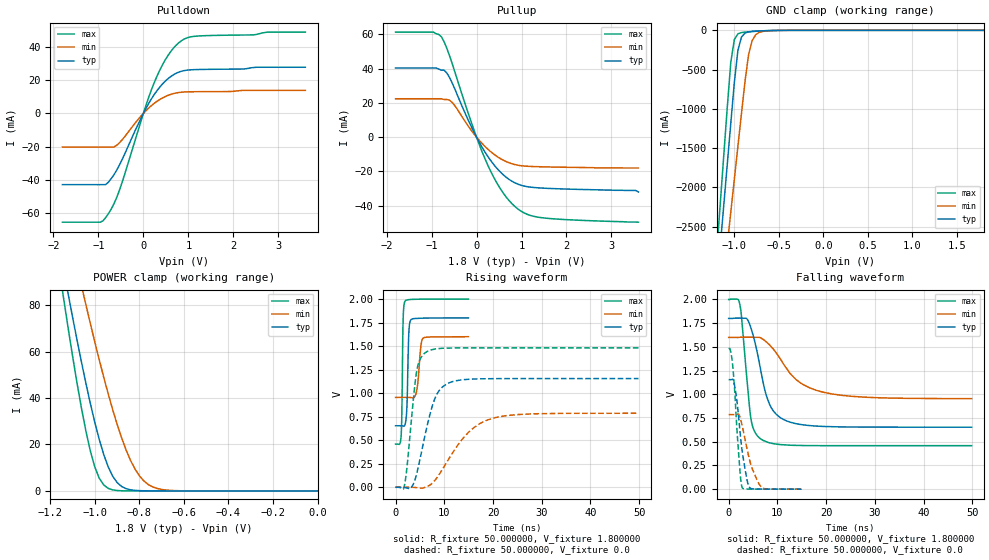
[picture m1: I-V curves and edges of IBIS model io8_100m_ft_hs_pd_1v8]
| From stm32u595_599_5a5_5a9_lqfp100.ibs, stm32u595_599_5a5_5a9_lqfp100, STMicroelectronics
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|   Model io8_100m_ft_hs_pd_1v8
[Model]  io8_100m_ft_hs_pd_1v8
Model_type I/O
Polarity   Non-Inverting
Enable   Active-Low
Vinl =   0.540000V
Vinh =   1.260000V
Vmeas =  0.900000V
Cref =   50.000000pF
Rref =   100.000000M
Vref =   0.0V
C_comp   3.148300pF   3.147400pF   3.196500pF
[Temperature Range]   25.000000   0.140000k   -40.000000
[Pullup Reference]   1.800000V   1.600000V   2.000000V
[Pulldown Reference]   0.0V   0.0V   0.0V
[POWER Clamp Reference]   1.800000V   1.600000V   2.000000V
[GND Clamp Reference]   0.0V   0.0V   0.0V
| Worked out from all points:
|   slope of the pulldown table from 0 to 0.27 V, typ, clamps not added: 21.7 ohm
|   slope of the pullup table from 0 to 0.27 V, typ, clamps not added: 22.6 ohm
|   GND clamp passes 1 mA (typ) near -0.51 V on its own axis
|   POWER clamp passes 1 mA (typ) near -0.86 V on its own axis
|   rising waveform, R_fixture 50.000000, V_fixture 1.800000: 20-80 % time 321ps typ, 635ps min, 233ps max; typ from 0.654 V to 1.8 V
|   rising waveform, R_fixture 50.000000, V_fixture 0.0: 20-80 % time 3.21ns typ, 6.77ns min, 1.69ns max; typ from 0 V to 1.15 V
|   falling waveform, R_fixture 50.000000, V_fixture 1.800000: 20-80 % time 3.21ns typ, 6.74ns min, 1.65ns max; typ from 1.8 V to 0.654 V
|   falling waveform, R_fixture 50.000000, V_fixture 0.0: 20-80 % time 1.6ns typ, 2.38ns min, 1.14ns max; typ from 1.15 V to 0 V
[Pulldown]
|Voltage   I(typ)   I(min)   I(max)
-1.8V     -42.74mA   -20.21mA   -65.25mA
-960mV    -42.74mA   -20.21mA   -65.25mA
-780mV    -41.3mA    -20.21mA   -60.25mA
-660mV    -37mA      -20.2mA    -54.5mA
-540mV    -31.39mA   -17.82mA   -46.65mA
0V        0A         100fA      0A
240mV     11.28mA    6.002mA    18.38mA
480mV     19.17mA    10.02mA    31.83mA
780mV     24.67mA    12.5mA     42.21mA
960mV     25.9mA     12.9mA     45.21mA
1.14V     26.24mA    12.99mA    46.23mA
3.6V      27.67mA    13.81mA    48.75mA
[Pullup]
|Voltage   I(typ)   I(min)   I(max)
-1.8V     40.32mA    22.37mA    61.24mA
-960mV    40.32mA    22.37mA    61.24mA
-780mV    39.04mA    22.37mA    58.49mA
-660mV    37.4mA     21.92mA    51.77mA
-540mV    31.51mA    20.18mA    42.78mA
-120mV    6.338mA    4.065mA    8.965mA
240mV     -10.82mA   -6.752mA   -15.73mA
540mV     -20.62mA   -12.68mA   -30.5mA
900mV     -27.22mA   -16.28mA   -41.49mA
1.14V     -28.94mA   -17mA      -45.14mA
1.5V      -29.77mA   -17.34mA   -47.14mA
3.6V      -32mA      -18mA      -49.6mA
[GND_clamp]
|Voltage   I(typ)   I(min)   I(max)
-1.8V     -9.707A    -9.942A    -9.774A
-1.2V     -3.309A    -4.006A    -2.865A
-1.16V    -2.777A    -3.584A    -2.239A
-1.12V    -2.246A    -3.162A    -1.614A
-1.04V    -1.186A    -2.319A    -408.7mA
-1V       -663.9mA   -1.898A    -117.8mA
-960mV    -254mA     -1.478A    -45.15mA
-920mV    -86.04mA   -1.06A     -28.6mA
-840mV    -19.13mA   -308.9mA   -18.75mA
-800mV    -13.4mA    -130.8mA   -15.33mA
-720mV    -7.959mA   -25.38mA   -9.395mA
1.8V      45.71uA    33.33uA    56.11uA
[POWER_clamp]
|Voltage   I(typ)   I(min)   I(max)
-1.8V     470.8mA    433.7mA    554.6mA
-1.14V    95.25mA    122.7mA    82.82mA
-1.12V    84.97mA    114mA      70.27mA
-1.06V    55.51mA    88.42mA    35.67mA
-1.04V    46.34mA    80.15mA    25.76mA
-1V       29.51mA    64.13mA    10.3mA
-940mV    10.39mA    41.86mA    1.109mA
-900mV    3.624mA    28.77mA    182.8uA
-840mV    490.7uA    13.24mA    11.35uA
-800mV    116.8uA    6.532mA    1.77uA
-740mV    13.2uA     1.723mA    109.3nA
0V        0A         18.72nA    0A
[Ramp]
| variable   typ   min   max
dV/dt_r  0.69258/3.20144n   0.47165/6.75160n   0.88830/1.68845n
dV/dt_f  0.68753/3.20925n   0.38675/6.71993n   0.92452/1.65194n
R_load = 50.000000
[Rising Waveform]
R_fixture= 50.000000
V_fixture= 1.800000
V_fixture_min= 1.600000
V_fixture_max= 2.000000
|time   V(typ)   V(min)   V(max)
0s        653.5mV    954.4mV    458.5mV
1.141ns   653.4mV    954.4mV    543mV
1.562ns   650.5mV    954.4mV    1.789V
1.922ns   663.2mV    954.4mV    1.974V
2.312ns   831mV      954.4mV    1.989V
2.763ns   1.673V     954.2mV    1.994V
3.123ns   1.777V     953.3mV    1.995V
4.324ns   1.794V     1.025V     1.997V
5.556ns   1.796V     1.578V     1.998V
14.95ns   1.799V     1.599V     1.999V
[Rising Waveform]
R_fixture= 50.000000
V_fixture= 0.0
V_fixture_min= 0.0
V_fixture_max= 0.0
|time   V(typ)   V(min)   V(max)
0s        3.152uV    2.986uV    1.193uV
1.802ns   -1.584mV   519.2nV    12.74mV
3.103ns   -9.114mV   131.7uV    631.5mV
4.404ns   157.9mV    -4.259mV   1.252V
6.507ns   658.5mV    9.259mV    1.443V
8.008ns   933.5mV    69.3mV     1.467V
9.61ns    1.065V     190mV      1.476V
14.41ns   1.145V     553.3mV    1.48V
18.72ns   1.153V     711.6mV    1.48V
49.85ns   1.154V     786.2mV    1.48V
[Falling Waveform]
R_fixture= 50.000000
V_fixture= 1.800000
V_fixture_min= 1.600000
V_fixture_max= 2.000000
|time   V(typ)   V(min)   V(max)
0s        1.799V     1.599V     1.999V
2.202ns   1.803V     1.601V     1.965V
2.603ns   1.803V     1.602V     1.834V
4.605ns   1.693V     1.602V     732.1mV
7.007ns   1.141V     1.581V     515.5mV
8.408ns   892.7mV    1.519V     488.5mV
10.11ns   773.3mV    1.411V     473mV
13.91ns   689.5mV    1.151V     461.5mV
18.52ns   663.5mV    1.034V     458.9mV
49.85ns   653.5mV    954.4mV    458.5mV
[Falling Waveform]
R_fixture= 50.000000
V_fixture= 0.0
V_fixture_min= 0.0
V_fixture_max= 0.0
|time   V(typ)   V(min)   V(max)
0s        1.154V     786.2mV    1.48V
600.6ps   1.155V     786.2mV    1.397V
1.231ns   1.089V     786.1mV    1.042V
1.682ns   934.2mV    787.1mV    641.3mV
2.252ns   644.5mV    769.5mV    233.5mV
2.523ns   507.6mV    722.5mV    79.44mV
2.763ns   404.1mV    670.8mV    18.33mV
4.144ns   29.52mV    339mV      1.272mV
6.787ns   961.9uV    18.43mV    374.8uV
14.95ns   3.152uV    2.986uV    1.193uV
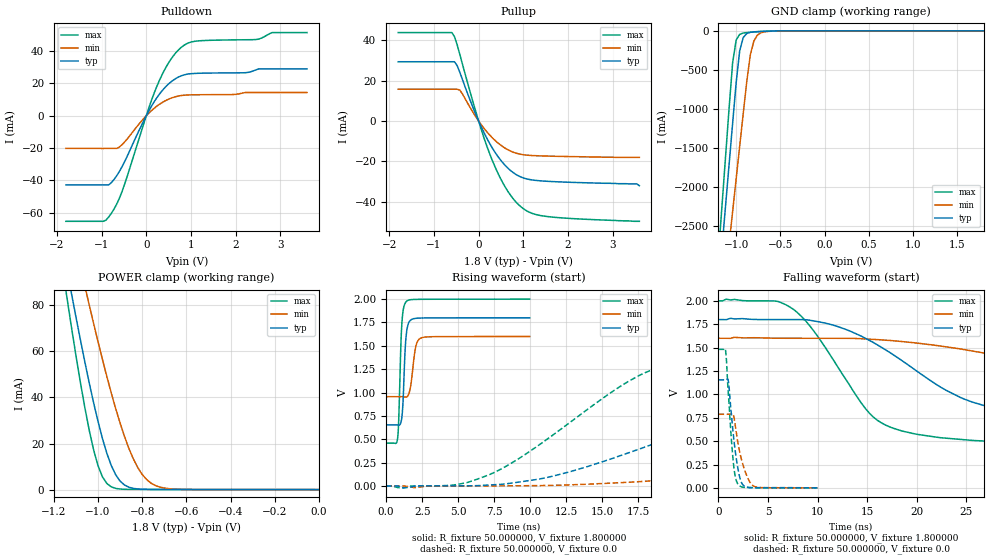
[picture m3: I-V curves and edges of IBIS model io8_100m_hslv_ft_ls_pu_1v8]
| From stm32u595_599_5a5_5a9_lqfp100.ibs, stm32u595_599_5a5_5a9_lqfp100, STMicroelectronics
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|   Model io8_100m_hslv_ft_ls_pu_1v8
[Model]  io8_100m_hslv_ft_ls_pu_1v8
Model_type I/O
Polarity   Non-Inverting
Enable   Active-Low
Vinl =   0.540000V
Vinh =   1.260000V
Vmeas =  0.900000V
Cref =   50.000000pF
Rref =   100.000000M
Vref =   0.0V
C_comp   3.235100pF   3.233100pF   3.282800pF
[Temperature Range]   25.000000   0.140000k   -40.000000
[Pullup Reference]   1.800000V   1.600000V   2.000000V
[Pulldown Reference]   0.0V   0.0V   0.0V
[POWER Clamp Reference]   1.800000V   1.600000V   2.000000V
[GND Clamp Reference]   0.0V   0.0V   0.0V
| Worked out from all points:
|   slope of the pulldown table from 0 to 0.27 V, typ, clamps not added: 21.7 ohm
|   slope of the pullup table from 0 to 0.27 V, typ, clamps not added: 22.6 ohm
|   GND clamp passes 1 mA (typ) near -0.51 V on its own axis
|   POWER clamp passes 1 mA (typ) near -0.86 V on its own axis
|   rising waveform, R_fixture 50.000000, V_fixture 1.800000: 20-80 % time 202ps typ, 314ps min, 189ps max; typ from 0.655 V to 1.8 V
|   rising waveform, R_fixture 50.000000, V_fixture 0.0: 20-80 % time 14.5ns typ, 29.3ns min, 8.35ns max; typ from 0.001 V to 1.16 V
|   falling waveform, R_fixture 50.000000, V_fixture 1.800000: 20-80 % time 11.4ns typ, 24.9ns min, 6.02ns max; typ from 1.8 V to 0.655 V
|   falling waveform, R_fixture 50.000000, V_fixture 0.0: 20-80 % time 736ps typ, 1.01ns min, 582ps max; typ from 1.16 V to 0.001 V
[Pulldown]
|Voltage   I(typ)   I(min)   I(max)
-1.8V     -42.74mA   -20.21mA   -65.25mA
-960mV    -42.74mA   -20.21mA   -65.25mA
-780mV    -41.3mA    -20.21mA   -60.25mA
-540mV    -31.39mA   -17.82mA   -46.65mA
0V        0A         0A         0A
240mV     11.28mA    6.001mA    18.38mA
480mV     19.17mA    10.02mA    31.83mA
780mV     24.67mA    12.49mA    42.21mA
1.14V     26.24mA    12.99mA    46.23mA
2.46V     28.42mA    14.38mA    47.14mA
2.82V     28.99mA    14.38mA    51.44mA
3.6V      28.99mA    14.38mA    51.44mA
[Pullup]
|Voltage   I(typ)   I(min)   I(max)
-1.8V     29.28mA    15.71mA    43.7mA
-600mV    29.28mA    15.71mA    43.7mA
-540mV    29.28mA    15.71mA    41.71mA
-420mV    24.04mA    15.23mA    32.87mA
0V        630fA      250pA      10fA
300mV     -13.1mA    -8.157mA   -19.11mA
600mV     -22.1mA    -13.53mA   -32.82mA
780mV     -25.61mA   -15.48mA   -38.6mA
960mV     -27.82mA   -16.55mA   -42.66mA
1.2V      -29.16mA   -17.08mA   -45.68mA
1.56V     -29.85mA   -17.37mA   -47.3mA
3.6V      -32mA      -18mA      -49.6mA
[GND_clamp]
|Voltage   I(typ)   I(min)   I(max)
-1.8V     -9.707A    -9.942A    -9.774A
-1.2V     -3.309A    -4.006A    -2.864A
-1.16V    -2.777A    -3.584A    -2.239A
-1.12V    -2.246A    -3.162A    -1.614A
-1.04V    -1.186A    -2.319A    -408.6mA
-1V       -663.9mA   -1.898A    -117.8mA
-960mV    -254mA     -1.478A    -45.14mA
-920mV    -86.03mA   -1.06A     -28.58mA
-840mV    -19.12mA   -308.9mA   -18.74mA
-800mV    -13.39mA   -130.8mA   -15.31mA
-720mV    -7.948mA   -25.37mA   -9.381mA
1.8V      0A         14.95nA    0A
[POWER_clamp]
|Voltage   I(typ)   I(min)   I(max)
-1.8V     470.9mA    433.7mA    554.6mA
-1.14V    95.28mA    122.7mA    82.88mA
-1.12V    85mA       114mA      70.34mA
-1.06V    55.55mA    88.43mA    35.73mA
-1.04V    46.38mA    80.17mA    25.83mA
-1V       29.54mA    64.14mA    10.37mA
-940mV    10.43mA    41.88mA    1.177mA
-900mV    3.66mA     28.79mA    250.5uA
-840mV    527.2uA    13.26mA    94.87uA
-800mV    153.8uA    6.55mA     88.76uA
-740mV    60.08uA    1.741mA    70.81uA
0V        0A         18.15nA    0A
[Ramp]
| variable   typ   min   max
dV/dt_r  0.69287/14.45255n   0.47190/29.25934n   0.88855/8.34234n
dV/dt_f  0.68715/11.33826n   0.38628/24.86071n   0.92439/6.00264n
R_load = 50.000000
[Rising Waveform]
R_fixture= 50.000000
V_fixture= 1.800000
V_fixture_min= 1.600000
V_fixture_max= 2.000000
|time   V(typ)   V(min)   V(max)
0s        654.8mV    956.1mV    459.3mV
780.8ps   653.9mV    956mV      496.2mV
860.9ps   651.3mV    956.1mV    664.2mV
1.081ns   724.7mV    956mV      1.715V
1.201ns   1.006V     955.1mV    1.898V
1.401ns   1.626V     952.2mV    1.974V
1.662ns   1.77V      1.037V     1.993V
2.082ns   1.795V     1.507V     1.997V
2.422ns   1.798V     1.584V     1.998V
9.97ns    1.8V       1.6V       2V
[Rising Waveform]
R_fixture= 50.000000
V_fixture= 0.0
V_fixture_min= 0.0
V_fixture_max= 0.0
|time   V(typ)   V(min)   V(max)
0s        611.3uV    688.3uV    577.8uV
6.006ns   2.833mV    1.347mV    56.51mV
11.21ns   93.11mV    6.136mV    504.8mV
18.02ns   420mV      51.05mV    1.215V
21.62ns   613.6mV    101.4mV    1.36V
26.83ns   851.8mV    194.8mV    1.435V
34.03ns   1.037V     335.6mV    1.468V
40.84ns   1.103V     457.1mV    1.478V
71.67ns   1.153V     735mV      1.482V
199.4ns   1.155V     787.4mV    1.482V
[Falling Waveform]
R_fixture= 50.000000
V_fixture= 1.800000
V_fixture_min= 1.600000
V_fixture_max= 2.000000
|time   V(typ)   V(min)   V(max)
0s        1.8V       1.6V       2V
6.807ns   1.8V       1.6V       1.958V
9.209ns   1.793V     1.6V       1.732V
14.41ns   1.622V     1.595V     905.7mV
16.02ns   1.53V      1.586V     723.5mV
19.62ns   1.278V     1.553V     581.6mV
25.63ns   916.7mV    1.463V     507.7mV
42.04ns   705mV      1.156V     465.6mV
64.06ns   663.4mV    1.021V     459.9mV
199.4ns   654.8mV    956.1mV    459.3mV
[Falling Waveform]
R_fixture= 50.000000
V_fixture= 0.0
V_fixture_min= 0.0
V_fixture_max= 0.0
|time   V(typ)   V(min)   V(max)
0s        1.155V     787.4mV    1.482V
720.7ps   1.155V     787.5mV    1.464V
1.001ns   1.137V     787.7mV    995.7mV
1.461ns   604.9mV    790.8mV    312.2mV
1.662ns   417.7mV    689.2mV    137.8mV
1.982ns   193.9mV    468.8mV    37.7mV
2.462ns   32.46mV    248.8mV    7.98mV
3.043ns   5.176mV    85.74mV    3.168mV
3.584ns   1.593mV    17.78mV    2.652mV
9.97ns    611.3uV    688.3uV    577.8uV
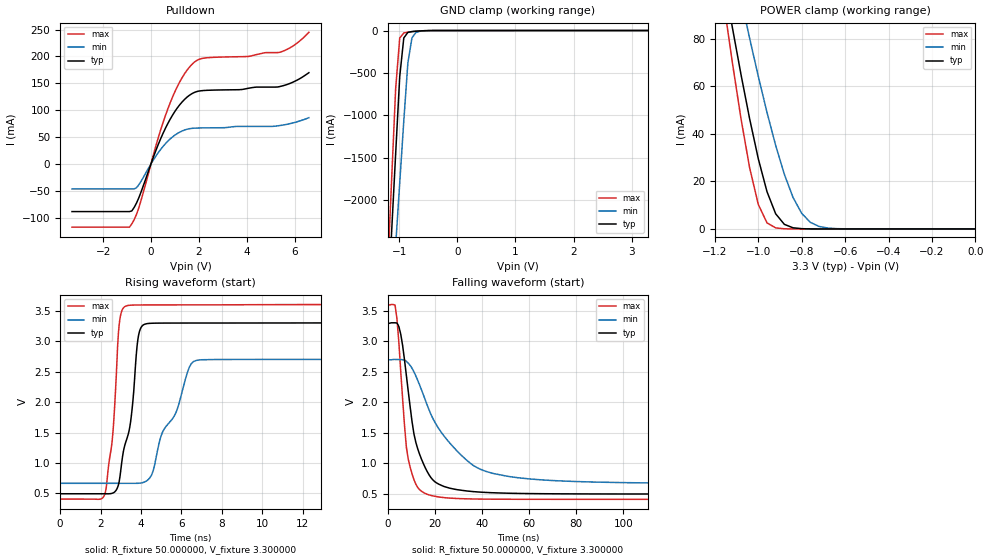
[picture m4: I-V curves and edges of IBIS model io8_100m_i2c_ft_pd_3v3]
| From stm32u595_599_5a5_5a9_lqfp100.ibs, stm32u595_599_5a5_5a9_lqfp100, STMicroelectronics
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|   Model io8_100m_i2c_ft_pd_3v3
[Model]  io8_100m_i2c_ft_pd_3v3
Model_type I/O_open_drain
Polarity   Non-Inverting
Enable   Active-Low
Vinl =   0.990000V
Vinh =   2.310000V
Vmeas =  1.600000V
Cref =   50.000000pF
Rref =   1.000000
Vref =   1.650000V
C_comp   3.320400pF   3.288500pF   3.361100pF
[Temperature Range]   25.000000   0.140000k   -40.000000
[Pullup Reference]   3.300000V   2.700000V   3.600000V
[Pulldown Reference]   0.0V   0.0V   0.0V
[POWER Clamp Reference]   3.300000V   2.700000V   3.600000V
[GND Clamp Reference]   0.0V   0.0V   0.0V
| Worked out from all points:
|   slope of the pulldown table from 0 to 0.495 V, typ, clamps not added: 8.84 ohm
|   GND clamp passes 1 mA (typ) near -0.50 V on its own axis
|   POWER clamp passes 1 mA (typ) near -0.85 V on its own axis
|   rising waveform, R_fixture 50.000000, V_fixture 3.300000: 20-80 % time 691ps typ, 1.39ns min, 418ps max; typ from 0.496 V to 3.3 V
|   falling waveform, R_fixture 50.000000, V_fixture 3.300000: 20-80 % time 7.46ns typ, 19.4ns min, 4.08ns max; typ from 3.3 V to 0.496 V
[Pulldown]
|Voltage   I(typ)   I(min)   I(max)
-3.3V     -88.61mA   -46.48mA   -117.6mA
-900mV    -88.61mA   -46.48mA   -117.6mA
-700mV    -80.76mA   -46.48mA   -103.5mA
-500mV    -62.15mA   -38.24mA   -80.45mA
300mV     35.76mA    20.75mA    48.1mA
800mV     83.04mA    46.39mA    113.5mA
1.3V      115.2mA    61.33mA    160.4mA
1.8V      132.8mA    66.57mA    188.9mA
2.3V      136.9mA    67.16mA    197.4mA
5.4V      144.2mA    71.57mA    207.9mA
6V        153.6mA    77.1mA     221.4mA
6.6V      169.8mA    86.1mA     244.9mA
[GND_clamp]
|Voltage   I(typ)   I(min)   I(max)
-3.3V     -9.848A    -9.957A    -9.458A
-1.2V     -3.312A    -4.013A    -2.863A
-1.13V    -2.381A    -3.274A    -1.769A
-1.06V    -1.452A    -2.535A    -684.8mA
-990mV    -542.9mA   -1.798A    -88.04mA
-920mV    -87.13mA   -1.064A    -28.45mA
-850mV    -22.11mA   -382.4mA   -19.62mA
-780mV    -11.98mA   -86.98mA   -13.73mA
-710mV    -7.63mA    -22.27mA   -8.759mA
-640mV    -4.504mA   -7.781mA   -4.831mA
-360mV    -39.8uA    -178.9uA   -19.56uA
3.28V     83.52uA    56.87uA    102.4uA
[POWER_clamp]
|Voltage   I(typ)   I(min)   I(max)
-3.28V    1.355A     1.167A     1.664A
-1.16V    105.7mA    131.6mA    95.69mA
-1.12V    84.97mA    114mA      70.27mA
-1.08V    65.05mA    96.83mA    46.54mA
-1.04V    46.34mA    80.15mA    25.76mA
-1V       29.51mA    64.13mA    10.3mA
-960mV    15.69mA    48.99mA    2.571mA
-920mV    6.373mA    35.1mA     455.6uA
-840mV    490.7uA    13.24mA    11.36uA
-760mV    27.33uA    2.767mA    276.6nA
-640mV    346.6nA    134.1uA    15.62nA
0V        0A         19.91nA    0A
[Ramp]
| variable   typ   min   max
dV/dt_r  1.68215/0.76969n   1.21927/1.44587n   1.91450/0.52866n
dV/dt_f  1.68215/7.44752n   1.21927/19.36738n   1.91450/4.06989n
R_load = 50.000000
[Rising Waveform]
R_fixture= 50.000000
V_fixture= 3.300000
V_fixture_min= 2.700000
V_fixture_max= 3.600000
|time   V(typ)   V(min)   V(max)
0s        495.6mV    667.1mV    408.3mV
2.202ns   495.4mV    667mV      482.9mV
2.603ns   507mV      666.7mV    1.467V
2.923ns   698.5mV    666.4mV    3.276V
3.243ns   1.34V      666.2mV    3.572V
3.524ns   1.776V     666.3mV    3.589V
3.844ns   3.022V     667.3mV    3.591V
4.164ns   3.273V     687.3mV    3.592V
6.727ns   3.295V     2.681V     3.593V
19.94ns   3.299V     2.699V     3.599V
[Falling Waveform]
R_fixture= 50.000000
V_fixture= 3.300000
V_fixture_min= 2.700000
V_fixture_max= 3.600000
|time   V(typ)   V(min)   V(max)
0s        3.299V     2.699V     3.599V
3.203ns   3.307V     2.705V     3.598V
5.606ns   3.122V     2.704V     2.512V
8.008ns   2.44V      2.673V     1.263V
9.61ns    1.926V     2.607V     935.3mV
12.81ns   1.238V     2.362V     602.9mV
19.22ns   728.1mV    1.738V     464.7mV
37.64ns   531.3mV    935.6mV    413.4mV
64.06ns   501.1mV    731.4mV    408.7mV
398.8ns   495.6mV    667.1mV    408.3mV
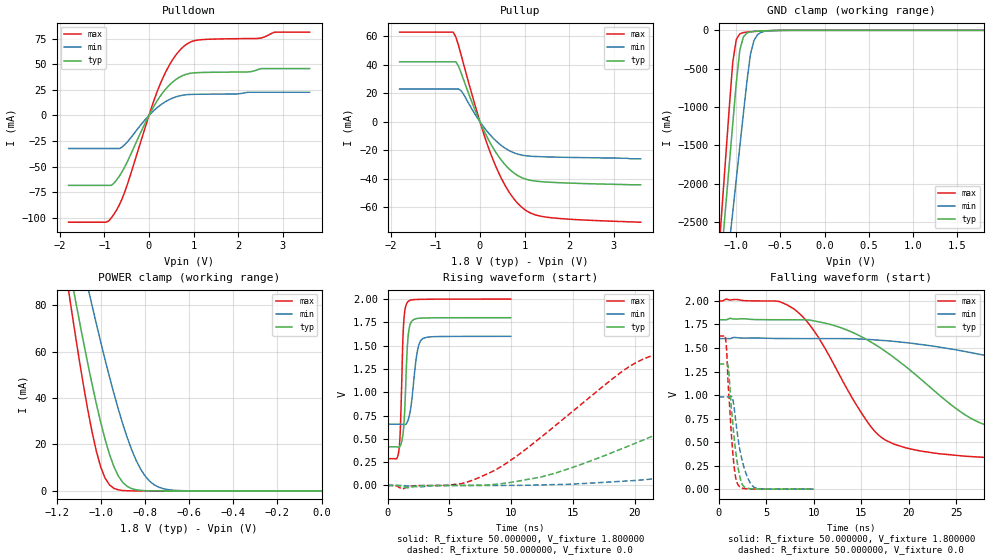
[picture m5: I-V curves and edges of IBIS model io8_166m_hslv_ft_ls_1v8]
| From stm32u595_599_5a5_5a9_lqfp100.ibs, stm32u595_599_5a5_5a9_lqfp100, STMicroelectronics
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|   Model io8_166m_hslv_ft_ls_1v8
[Model]  io8_166m_hslv_ft_ls_1v8
Model_type I/O
Polarity   Non-Inverting
Enable   Active-Low
Vinl =   0.540000V
Vinh =   1.260000V
Vmeas =  0.900000V
Cref =   50.000000pF
Rref =   100.000000M
Vref =   0.0V
C_comp   3.358300pF   3.352700pF   3.400300pF
[Temperature Range]   25.000000   0.140000k   -40.000000
[Pullup Reference]   1.800000V   1.600000V   2.000000V
[Pulldown Reference]   0.0V   0.0V   0.0V
[POWER Clamp Reference]   1.800000V   1.600000V   2.000000V
[GND Clamp Reference]   0.0V   0.0V   0.0V
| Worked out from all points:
|   slope of the pulldown table from 0 to 0.27 V, typ, clamps not added: 13.6 ohm
|   slope of the pullup table from 0 to 0.27 V, typ, clamps not added: 15.9 ohm
|   GND clamp passes 1 mA (typ) near -0.51 V on its own axis
|   POWER clamp passes 1 mA (typ) near -0.86 V on its own axis
|   rising waveform, R_fixture 50.000000, V_fixture 1.800000: 20-80 % time 278ps typ, 482ps min, 228ps max; typ from 0.414 V to 1.8 V
|   rising waveform, R_fixture 50.000000, V_fixture 0.0: 20-80 % time 16ns typ, 33.3ns min, 9.35ns max; typ from 0 V to 1.33 V
|   falling waveform, R_fixture 50.000000, V_fixture 1.800000: 20-80 % time 11.1ns typ, 27.4ns min, 6.1ns max; typ from 1.8 V to 0.414 V
|   falling waveform, R_fixture 50.000000, V_fixture 0.0: 20-80 % time 787ps typ, 1.05ns min, 621ps max; typ from 1.33 V to 0 V
[Pulldown]
|Voltage   I(typ)   I(min)   I(max)
-1.8V     -68.38mA   -32.32mA   -104.4mA
-960mV    -68.38mA   -32.32mA   -104.4mA
-780mV    -66.08mA   -32.32mA   -96.42mA
-540mV    -50.22mA   -28.51mA   -74.66mA
0V        0A         -700fA     0A
240mV     18.04mA    9.599mA    29.42mA
480mV     30.68mA    16.02mA    50.95mA
780mV     39.48mA    19.98mA    67.57mA
1.14V     41.99mA    20.78mA    74.01mA
2.46V     45.09mA    22.69mA    75.45mA
2.82V     45.91mA    22.69mA    81.58mA
3.6V      45.91mA    22.69mA    81.58mA
[Pullup]
|Voltage   I(typ)   I(min)   I(max)
-1.8V     42.16mA    23.02mA    63.04mA
-600mV    42.16mA    23.02mA    63.04mA
-540mV    42.16mA    23.02mA    59.55mA
-420mV    34.21mA    21.82mA    46.75mA
0V        630fA      250pA      0A
300mV     -18.63mA   -11.6mA    -27.18mA
600mV     -31.41mA   -19.24mA   -46.67mA
780mV     -36.41mA   -22mA      -54.88mA
960mV     -39.54mA   -23.51mA   -60.64mA
1.2V      -41.44mA   -24.28mA   -64.94mA
1.56V     -42.42mA   -24.69mA   -67.24mA
3.6V      -44.2mA    -26mA      -70.5mA
[GND_clamp]
|Voltage   I(typ)   I(min)   I(max)
-1.8V     -9.908A    -9.683A    -9.994A
-1.2V     -3.383A    -4.084A    -2.934A
-1.16V    -2.841A    -3.655A    -2.294A
-1.12V    -2.299A    -3.226A    -1.656A
-1.04V    -1.218A    -2.369A    -414.2mA
-1V       -684.7mA   -1.941A    -119.2mA
-960mV    -257.2mA   -1.514A    -45.66mA
-920mV    -87.03mA   -1.089A    -28.93mA
-840mV    -19.35mA   -312.8mA   -18.97mA
-800mV    -13.55mA   -132.4mA   -15.49mA
-720mV    -8.042mA   -25.67mA   -9.491mA
1.8V      0A         13.64nA    0A
[POWER_clamp]
|Voltage   I(typ)   I(min)   I(max)
-1.8V     470.8mA    433.7mA    554.6mA
-1.14V    95.25mA    122.7mA    82.82mA
-1.12V    84.97mA    114mA      70.27mA
-1.06V    55.51mA    88.42mA    35.67mA
-1.04V    46.34mA    80.15mA    25.76mA
-1V       29.51mA    64.13mA    10.3mA
-940mV    10.39mA    41.86mA    1.109mA
-900mV    3.624mA    28.77mA    182.8uA
-840mV    490.7uA    13.24mA    11.35uA
-800mV    116.8uA    6.532mA    1.77uA
-740mV    13.2uA     1.724mA    109.3nA
0V        0A         18.75nA    0A
[Ramp]
| variable   typ   min   max
dV/dt_r  0.79770/15.96776n   0.58803/33.28162n   0.97668/9.34325n
dV/dt_f  0.83164/11.13166n   0.56522/27.38376n   1.02770/6.08731n
R_load = 50.000000
[Rising Waveform]
R_fixture= 50.000000
V_fixture= 1.800000
V_fixture_min= 1.600000
V_fixture_max= 2.000000
|time   V(typ)   V(min)   V(max)
0s        413.9mV    656.9mV    287.2mV
920.9ps   411mV      657mV      378.3mV
1.041ns   428.2mV    657mV      634.5mV
1.221ns   525.4mV    656.4mV    1.494V
1.301ns   620.3mV    655mV      1.74V
1.622ns   1.53V      687.7mV    1.968V
1.862ns   1.739V     817.3mV    1.989V
2.382ns   1.791V     1.418V     1.996V
2.803ns   1.796V     1.571V     1.997V
9.97ns    1.8V       1.6V       2V
[Rising Waveform]
R_fixture= 50.000000
V_fixture= 0.0
V_fixture_min= 0.0
V_fixture_max= 0.0
|time   V(typ)   V(min)   V(max)
0s        1.85nV     146.7nV    1.205nV
6.006ns   -685uV     -463uV     20.54mV
8.408ns   8.79mV     -170.6uV   144.4mV
13.61ns   133.9mV    9.094mV    646mV
21.22ns   516.6mV    67.01mV    1.384V
32.03ns   1.048V     261.8mV    1.582V
43.64ns   1.248V     496.4mV    1.617V
60.46ns   1.31V      766.1mV    1.627V
78.08ns   1.326V     898.1mV    1.628V
199.4ns   1.33V      980.3mV    1.628V
[Falling Waveform]
R_fixture= 50.000000
V_fixture= 1.800000
V_fixture_min= 1.600000
V_fixture_max= 2.000000
|time   V(typ)   V(min)   V(max)
0s        1.8V       1.6V       2V
8.008ns   1.8V       1.6V       1.909V
10.41ns   1.78V      1.6V       1.625V
13.21ns   1.702V     1.6V       1.117V
17.62ns   1.458V     1.577V     516.9mV
26.03ns   782.4mV    1.46V      349.3mV
37.64ns   516.6mV    1.181V     306.1mV
50.45ns   456.7mV    907.3mV    293.1mV
69.27ns   427.4mV    759.7mV    288.3mV
199.4ns   413.9mV    656.9mV    287.2mV
[Falling Waveform]
R_fixture= 50.000000
V_fixture= 0.0
V_fixture_min= 0.0
V_fixture_max= 0.0
|time   V(typ)   V(min)   V(max)
0s        1.33V      980.3mV    1.628V
740.7ps   1.329V     980.4mV    1.592V
860.9ps   1.335V     980.4mV    1.446V
1.041ns   1.271V     980.4mV    1.051V
1.502ns   688.4mV    951.3mV    377.2mV
1.742ns   447.1mV    773.8mV    153.7mV
2.062ns   219.7mV    523.7mV    43.94mV
2.563ns   39.2mV     269.3mV    8.498mV
3.724ns   2.163mV    21.03mV    1.239mV
9.97ns    1.85nV     146.7nV    1.205nV
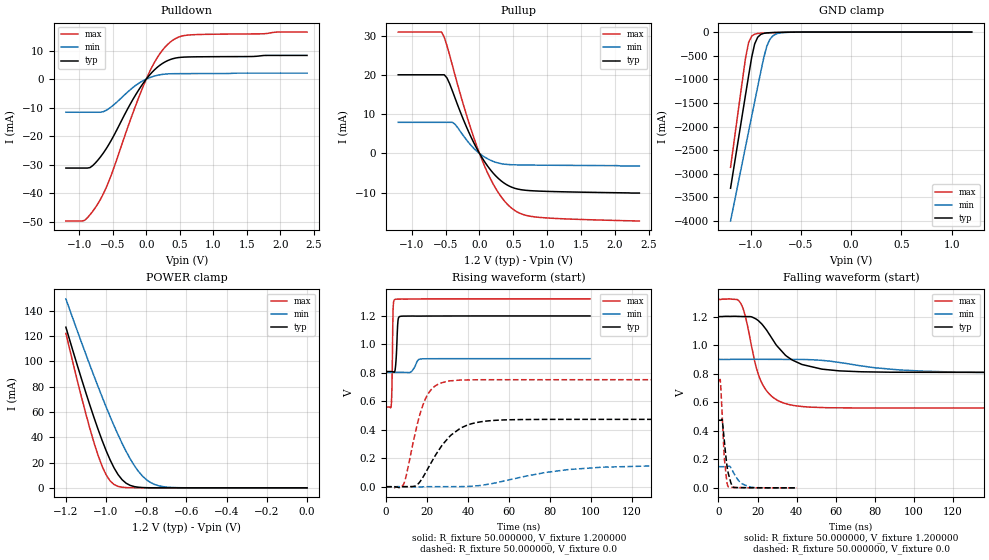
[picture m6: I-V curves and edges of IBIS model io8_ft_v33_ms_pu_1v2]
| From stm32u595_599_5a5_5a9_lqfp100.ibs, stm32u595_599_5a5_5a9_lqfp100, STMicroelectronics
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|   Model io8_ft_v33_ms_pu_1v2
[Model]  io8_ft_v33_ms_pu_1v2
Model_type I/O
Polarity   Non-Inverting
Enable   Active-Low
Vinl =   0.360000V
Vinh =   0.840000V
Vmeas =  0.600000V
Cref =   50.000000pF
Rref =   100.000000M
Vref =   0.0V
C_comp   2.887200pF   2.816900pF   2.935200pF
[Temperature Range]   25.000000   0.140000k   -40.000000
[Pullup Reference]   1.200000V   0.900000V   1.320000V
[Pulldown Reference]   0.0V   0.0V   0.0V
[POWER Clamp Reference]   1.200000V   0.900000V   1.320000V
[GND Clamp Reference]   0.0V   0.0V   0.0V
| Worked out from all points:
|   slope of the pulldown table from 0 to 0.18 V, typ, clamps not added: 40.7 ohm
|   slope of the pullup table from 0 to 0.18 V, typ, clamps not added: 39.5 ohm
|   GND clamp passes 1 mA (typ) near -0.51 V on its own axis
|   POWER clamp passes 1 mA (typ) near -0.86 V on its own axis
|   rising waveform, R_fixture 50.000000, V_fixture 1.200000: 20-80 % time 745ps typ, 2.06ns min, 445ps max; typ from 0.809 V to 1.2 V
|   rising waveform, R_fixture 50.000000, V_fixture 0.0: 20-80 % time 14.1ns typ, 33.7ns min, 7.83ns max; typ from 0.001 V to 0.474 V
|   falling waveform, R_fixture 50.000000, V_fixture 1.200000: 20-80 % time 15.4ns typ, 36.8ns min, 8.76ns max; typ from 1.2 V to 0.809 V
|   falling waveform, R_fixture 50.000000, V_fixture 0.0: 20-80 % time 2.5ns typ, 4.75ns min, 1.85ns max; typ from 0.474 V to 0.001 V
[Pulldown]
|Voltage   I(typ)   I(min)   I(max)
-1.2V     -31.16mA   -11.61mA   -49.71mA
-920mV    -31.16mA   -11.61mA   -49.49mA
-840mV    -31mA      -11.61mA   -47.54mA
-720mV    -28.32mA   -11.61mA   -43.58mA
-560mV    -22.95mA   -10.37mA   -35.89mA
-200mV    -7.146mA   -2.964mA   -11.89mA
0V        0A         0A         0A
160mV     4.047mA    1.298mA    7.361mA
360mV     6.869mA    1.87mA     13mA
480mV     7.543mA    1.91mA     14.69mA
640mV     7.765mA    1.923mA    15.46mA
2.4V      8.292mA    2.092mA    16.49mA
[Pullup]
|Voltage   I(typ)   I(min)   I(max)
-1.2V     20.06mA    7.936mA    30.96mA
-560mV    20.06mA    7.936mA    30.96mA
-480mV    19.26mA    7.936mA    27.49mA
-360mV    14.08mA    7.421mA    19.88mA
-160mV    5.494mA    2.767mA    8.045mA
40mV      -1.16mA    -508.1uA   -1.774mA
240mV     -5.73mA    -2.256mA   -8.953mA
360mV     -7.518mA   -2.715mA   -11.96mA
480mV     -8.639mA   -2.877mA   -14.04mA
640mV     -9.31mA    -2.942mA   -15.55mA
880mV     -9.601mA   -2.986mA   -16.29mA
2.36V     -10.1mA    -3.2mA     -17.23mA
[GND_clamp]
|Voltage   I(typ)   I(min)   I(max)
-1.2V     -3.305A    -3.998A    -2.862A
-1.05V    -1.316A    -2.418A    -539.3mA
-1.02V    -921mA     -2.103A    -218.8mA
-990mV    -539.5mA   -1.788A    -87.43mA
-960mV    -252.1mA   -1.474A    -44.36mA
-930mV    -110.5mA   -1.16A     -30.32mA
-870mV    -28.03mA   -549.1mA   -21.09mA
-840mV    -18.43mA   -305.6mA   -18.27mA
-810mV    -13.9mA    -159.7mA   -15.73mA
-780mV    -11.23mA   -82.35mA   -13.37mA
-600mV    -2.976mA   -4.272mA   -3.058mA
1.2V      0A         14.74nA    0A
[POWER_clamp]
|Voltage   I(typ)   I(min)   I(max)
-1.2V     127mA      149.4mA    122.2mA
-1.12V    84.98mA    114mA      70.29mA
-1.06V    55.52mA    88.42mA    35.69mA
-1.02V    37.64mA    72.04mA    17.19mA
-1V       29.52mA    64.13mA    10.33mA
-960mV    15.7mA     48.99mA    2.597mA
-900mV    3.636mA    28.77mA    209uA
-840mV    503.6uA    13.24mA    43.76uA
-800mV    129.7uA    6.535mA    43.76uA
-740mV    27.38uA    1.727mA    43.76uA
-620mV    25.25uA    82.57uA    35.67uA
0V        0A         17.33nA    0A
[Ramp]
| variable   typ   min   max
dV/dt_r  0.28389/14.07066n   88.99786m/33.69208n 0.45097/7.82172n
dV/dt_f  0.23437/15.35055n   57.82800m/36.76665n 0.45608/8.73825n
R_load = 50.000000
[Rising Waveform]
R_fixture= 50.000000
V_fixture= 1.200000
V_fixture_min= 0.900000
V_fixture_max= 1.320000
|time   V(typ)   V(min)   V(max)
0s        809.5mV    803.6mV    559.9mV
2.603ns   809.6mV    803.6mV    593.5mV
2.803ns   809.5mV    803.6mV    677.9mV
3.403ns   807.9mV    803.6mV    1.254V
4.204ns   809.5mV    803.6mV    1.315V
4.805ns   883.3mV    803.6mV    1.317V
5.806ns   1.17V      803.6mV    1.318V
6.807ns   1.197V     803.6mV    1.318V
17.22ns   1.199V     898.3mV    1.32V
99.7ns    1.2V       900mV      1.32V
[Rising Waveform]
R_fixture= 50.000000
V_fixture= 0.0
V_fixture_min= 0.0
V_fixture_max= 0.0
|time   V(typ)   V(min)   V(max)
0s        591.7uV    600.2uV    545.2uV
8.408ns   937.9uV    607.1uV    13.65mV
14.41ns   7.153mV    -387uV     389.8mV
19.22ns   97.29mV    512.7uV    617.7mV
24.02ns   219.6mV    820.6uV    708.8mV
30.63ns   346.6mV    989uV      743.2mV
40.24ns   436.1mV    2.616mV    750.9mV
57.06ns   469.5mV    38.73mV    752mV
105.7ns   473.7mV    137.7mV    752.1mV
299.1ns   473.8mV    149mV      752.1mV
[Falling Waveform]
R_fixture= 50.000000
V_fixture= 1.200000
V_fixture_min= 0.900000
V_fixture_max= 1.320000
|time   V(typ)   V(min)   V(max)
0s        1.2V       900mV      1.32V
11.41ns   1.201V     900.6mV    1.292V
13.81ns   1.2V       900.4mV    1.198V
19.22ns   1.183V     900.5mV    849.6mV
22.22ns   1.147V     900.5mV    734mV
28.23ns   1.029V     900.2mV    630.7mV
37.84ns   895.2mV    900mV      579.1mV
73.27ns   813.3mV    854.4mV    559.9mV
121.9ns   809.5mV    811mV      559.9mV
299.1ns   809.5mV    803.6mV    559.9mV
[Falling Waveform]
R_fixture= 50.000000
V_fixture= 0.0
V_fixture_min= 0.0
V_fixture_max= 0.0
|time   V(typ)   V(min)   V(max)
0s        473.8mV    149mV      752.1mV
961ps     473.5mV    149mV      750.2mV
1.922ns   473.6mV    149mV      504.1mV
2.963ns   332.9mV    149mV      219.4mV
4.164ns   175mV      148.8mV    56.81mV
4.805ns   115.5mV    150mV      11.63mV
7.688ns   4.012mV    107.4mV    3.041mV
11.37ns   1.991mV    36mV       2.296mV
16.98ns   1.595mV    4.038mV    1.073mV
39.88ns   591.7uV    600.2uV    545.2uV
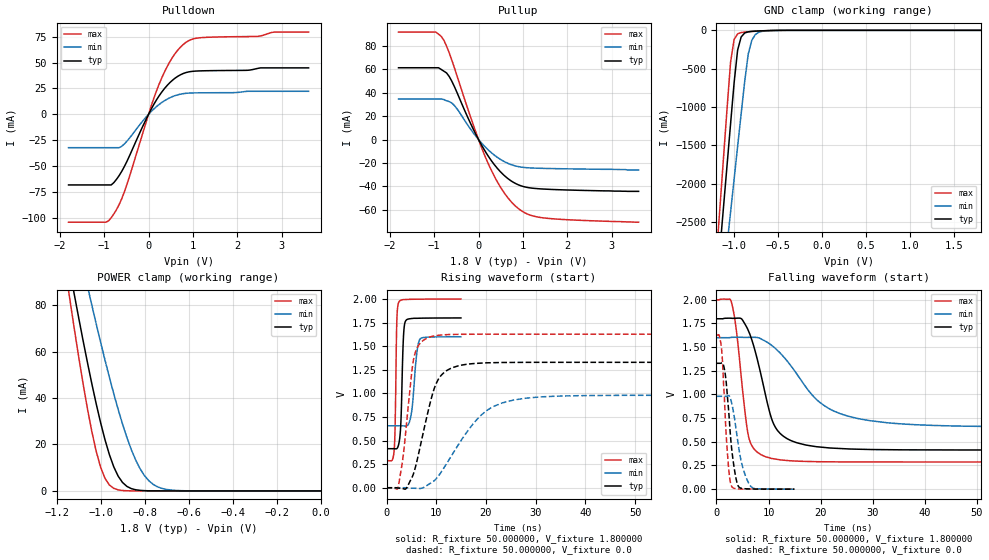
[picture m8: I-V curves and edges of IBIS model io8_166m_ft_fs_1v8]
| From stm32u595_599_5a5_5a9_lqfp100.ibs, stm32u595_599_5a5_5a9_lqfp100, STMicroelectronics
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|   Model io8_166m_ft_fs_1v8
[Model]  io8_166m_ft_fs_1v8
Model_type I/O
Polarity   Non-Inverting
Enable   Active-Low
Vinl =   0.540000V
Vinh =   1.260000V
Vmeas =  0.900000V
Cref =   50.000000pF
Rref =   100.000000M
Vref =   0.0V
C_comp   3.358200pF   3.352700pF   3.400300pF
[Temperature Range]   25.000000   0.140000k   -40.000000
[Pullup Reference]   1.800000V   1.600000V   2.000000V
[Pulldown Reference]   0.0V   0.0V   0.0V
[POWER Clamp Reference]   1.800000V   1.600000V   2.000000V
[GND Clamp Reference]   0.0V   0.0V   0.0V
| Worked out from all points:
|   slope of the pulldown table from 0 to 0.27 V, typ, clamps not added: 13.6 ohm
|   slope of the pullup table from 0 to 0.27 V, typ, clamps not added: 15.9 ohm
|   GND clamp passes 1 mA (typ) near -0.51 V on its own axis
|   POWER clamp passes 1 mA (typ) near -0.86 V on its own axis
|   rising waveform, R_fixture 50.000000, V_fixture 1.800000: 20-80 % time 455ps typ, 904ps min, 302ps max; typ from 0.414 V to 1.8 V
|   rising waveform, R_fixture 50.000000, V_fixture 0.0: 20-80 % time 3.64ns typ, 7.99ns min, 1.94ns max; typ from 0 V to 1.33 V
|   falling waveform, R_fixture 50.000000, V_fixture 1.800000: 20-80 % time 3.87ns typ, 9.13ns min, 2.06ns max; typ from 1.8 V to 0.414 V
|   falling waveform, R_fixture 50.000000, V_fixture 0.0: 20-80 % time 1.31ns typ, 1.87ns min, 982ps max; typ from 1.33 V to 0 V
[Pulldown]
|Voltage   I(typ)   I(min)   I(max)
-1.8V     -68.38mA   -32.32mA   -104.4mA
-960mV    -68.38mA   -32.32mA   -104.4mA
-780mV    -66.08mA   -32.32mA   -96.42mA
-660mV    -59.2mA    -32.31mA   -87.22mA
-540mV    -50.22mA   -28.51mA   -74.66mA
0V        0A         -200fA     0A
240mV     18.04mA    9.6mA      29.42mA
480mV     30.68mA    16.02mA    50.95mA
780mV     39.48mA    19.99mA    67.57mA
1.14V     41.99mA    20.78mA    74.01mA
2.82V     44.93mA    22.28mA    79.57mA
3.6V      44.93mA    22.28mA    79.57mA
[Pullup]
|Voltage   I(typ)   I(min)   I(max)
-1.8V     61.24mA    34.58mA    91.65mA
-960mV    61.24mA    34.58mA    91.65mA
-840mV    59.79mA    34.58mA    88.02mA
-720mV    56.82mA    33.03mA    79.77mA
-600mV    49.68mA    31.11mA    67.64mA
-120mV    9.014mA    5.781mA    12.75mA
240mV     -15.38mA   -9.6mA     -22.37mA
540mV     -29.31mA   -18.02mA   -43.36mA
900mV     -38.69mA   -23.13mA   -58.99mA
1.14V     -41.14mA   -24.16mA   -64.17mA
1.5V      -42.31mA   -24.64mA   -67mA
3.6V      -44.2mA    -26mA      -70.5mA
[GND_clamp]
|Voltage   I(typ)   I(min)   I(max)
-1.8V     -9.908A    -9.683A    -9.994A
-1.2V     -3.383A    -4.084A    -2.934A
-1.16V    -2.841A    -3.655A    -2.294A
-1.12V    -2.299A    -3.226A    -1.656A
-1.04V    -1.218A    -2.369A    -414.2mA
-1V       -684.7mA   -1.941A    -119.2mA
-960mV    -257.2mA   -1.514A    -45.66mA
-920mV    -87.03mA   -1.089A    -28.93mA
-840mV    -19.35mA   -312.8mA   -18.97mA
-800mV    -13.55mA   -132.4mA   -15.49mA
-720mV    -8.042mA   -25.67mA   -9.491mA
1.8V      0A         13.64nA    0A
[POWER_clamp]
|Voltage   I(typ)   I(min)   I(max)
-1.8V     470.8mA    433.7mA    554.6mA
-1.14V    95.25mA    122.7mA    82.82mA
-1.12V    84.97mA    114mA      70.27mA
-1.06V    55.51mA    88.42mA    35.67mA
-1.04V    46.34mA    80.15mA    25.76mA
-1V       29.51mA    64.13mA    10.3mA
-940mV    10.39mA    41.86mA    1.109mA
-900mV    3.624mA    28.77mA    182.8uA
-840mV    490.7uA    13.24mA    11.35uA
-800mV    116.8uA    6.532mA    1.77uA
-740mV    13.2uA     1.724mA    109.3nA
0V        0A         18.75nA    0A
[Ramp]
| variable   typ   min   max
dV/dt_r  0.79776/3.63462n   0.58816/7.98183n   0.97668/1.93020n
dV/dt_f  0.83164/3.86487n   0.56590/9.12432n   1.02770/2.04734n
R_load = 50.000000
[Rising Waveform]
R_fixture= 50.000000
V_fixture= 1.800000
V_fixture_min= 1.600000
V_fixture_max= 2.000000
|time   V(typ)   V(min)   V(max)
0s        413.9mV    656.8mV    287.2mV
1.592ns   413.4mV    656.9mV    435.2mV
2.072ns   415.1mV    656.9mV    1.764V
2.462ns   463.8mV    656.9mV    1.966V
2.883ns   685.4mV    656.7mV    1.987V
3.423ns   1.613V     655.8mV    1.994V
3.844ns   1.768V     654.4mV    1.995V
5.045ns   1.794V     803.7mV    1.998V
6.637ns   1.797V     1.567V     1.999V
14.95ns   1.8V       1.6V       2V
[Rising Waveform]
R_fixture= 50.000000
V_fixture= 0.0
V_fixture_min= 0.0
V_fixture_max= 0.0
|time   V(typ)   V(min)   V(max)
0s        2.607uV    2.599uV    1.309uV
2.402ns   -3.719mV   1.09uV     20.59mV
4.204ns   12.97mV    -977.4uV   776.7mV
5.806ns   216.9mV    -5.78mV    1.437V
8.809ns   906.3mV    47.08mV    1.599V
10.41ns   1.149V     123.4mV    1.616V
12.81ns   1.262V     317.8mV    1.624V
19.22ns   1.322V     778.1mV    1.627V
25.63ns   1.328V     930.5mV    1.628V
99.7ns    1.33V      980.3mV    1.628V
[Falling Waveform]
R_fixture= 50.000000
V_fixture= 1.800000
V_fixture_min= 1.600000
V_fixture_max= 2.000000
|time   V(typ)   V(min)   V(max)
0s        1.8V       1.6V       2V
2.803ns   1.806V     1.603V     1.989V
3.804ns   1.806V     1.605V     1.682V
6.206ns   1.663V     1.603V     543.6mV
9.61ns    945.7mV    1.556V     339.2mV
11.21ns   662.7mV    1.491V     318.7mV
13.61ns   531.7mV    1.351V     302.5mV
19.62ns   446.3mV    926.7mV    290mV
27.23ns   422mV      745mV      287.6mV
99.7ns    413.9mV    656.8mV    287.2mV
[Falling Waveform]
R_fixture= 50.000000
V_fixture= 0.0
V_fixture_min= 0.0
V_fixture_max= 0.0
|time   V(typ)   V(min)   V(max)
0s        1.33V      980.3mV    1.628V
510.5ps   1.329V     980.3mV    1.624V
961ps     1.333V     980.3mV    1.486V
1.562ns   1.255V     980.2mV    910mV
2.252ns   880.4mV    986.8mV    273.5mV
2.883ns   441.5mV    917.5mV    32.71mV
4.114ns   39.81mV    495mV      2.937mV
4.985ns   7.278mV    239.9mV    1.468mV
6.517ns   2.264mV    34.35mV    673.6uV
14.95ns   2.607uV    2.599uV    1.309uV
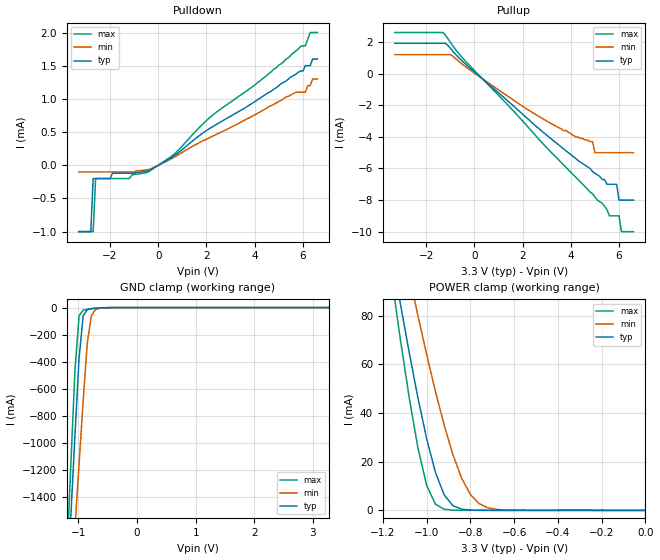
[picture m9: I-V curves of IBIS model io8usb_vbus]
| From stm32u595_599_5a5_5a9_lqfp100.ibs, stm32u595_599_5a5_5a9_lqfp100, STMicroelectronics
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|   Model io8usb_vbus
[Model]  io8usb_vbus
Model_type I/O
Polarity   Non-Inverting
Enable   Active-High
Vinl =   0.990000V
Vinh =   2.310000V
Vmeas =  1.650000V
Cref =   50.000000pF
Rref =   100.000000M
Vref =   0.0V
C_comp   3.171500pF   3.148500pF   3.202800pF
[Temperature Range]   25.000000   0.140000k   -40.000000
[Pullup Reference]   3.300000V   2.700000V   3.600000V
[Pulldown Reference]   0.0V   0.0V   0.0V
[POWER Clamp Reference]   3.300000V   2.700000V   3.600000V
[GND Clamp Reference]   0.0V   0.0V   0.0V
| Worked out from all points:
|   slope of the pulldown table from 0 to 0.495 V, typ, clamps not added: 4.81 kohm
|   slope of the pullup table from 0 to 0.495 V, typ, clamps not added: 753 ohm
|   GND clamp passes 1 mA (typ) near -0.53 V on its own axis
|   POWER clamp passes 1 mA (typ) near -0.85 V on its own axis
[Pulldown]
|Voltage   I(typ)   I(min)   I(max)
-3.3V     -1mA       -100uA     -1mA
-2.8V     -1mA       -100uA     -1mA
-2.7V     -200uA     -100uA     -1mA
-2.6V     -200uA     -100uA     -200uA
-1.2V     -120uA     -100uA     -200uA
-300mV    -61.73uA   -50.72uA   -73.84uA
700mV     151.7uA    129.9uA    180.8uA
2.3V      592.1uA    446.5uA    768.9uA
5.7V      1.37mA     1.1mA      1.72mA
6.1V      1.5mA      1.1mA      1.8mA
6.3V      1.5mA      1.2mA      2mA
6.6V      1.6mA      1.3mA      2mA
[Pullup]
|Voltage   I(typ)   I(min)   I(max)
-3.3V     1.93mA     1.209mA    2.61mA
-1.3V     1.93mA     1.209mA    2.61mA
-900mV    1.442mA    1.118mA    1.778mA
2.9V      -3.764mA   -2.906mA   -4.522mA
4.9V      -6.2mA     -4.3mA     -7.6mA
5V        -6.3mA     -5mA       -7.8mA
5.3V      -6.7mA     -5mA       -8.2mA
5.6V      -7mA       -5mA       -9mA
5.9V      -7mA       -5mA       -9mA
6V        -8mA       -5mA       -9mA
6.1V      -8mA       -5mA       -10mA
6.6V      -8mA       -5mA       -10mA
[GND_clamp]
|Voltage   I(typ)   I(min)   I(max)
-3.3V     -9.415A    -9.508A    -9.703A
-1.2V     -2.138A    -2.581A    -1.86A
-1.13V    -1.538A    -2.104A    -1.153A
-1.06V    -942.5mA   -1.629A    -463.6mA
-990mV    -370.9mA   -1.155A    -61.04mA
-920mV    -60.47mA   -689.2mA   -18.45mA
-850mV    -14.7mA    -261.7mA   -12.53mA
-780mV    -7.72mA    -59.92mA   -8.757mA
-710mV    -4.894mA   -15.16mA   -5.593mA
-640mV    -2.894mA   -5.172mA   -3.09mA
-360mV    -21.77uA   -117.9uA   -5.95uA
3.28V     0A         10.04nA    -7.986nA
[POWER_clamp]
|Voltage   I(typ)   I(min)   I(max)
-3.28V    1.355A     1.167A     1.664A
-1.16V    105.7mA    131.6mA    95.69mA
-1.12V    84.97mA    114mA      70.27mA
-1.08V    65.05mA    96.83mA    46.54mA
-1.04V    46.34mA    80.15mA    25.76mA
-1V       29.51mA    64.13mA    10.3mA
-960mV    15.69mA    48.99mA    2.571mA
-920mV    6.373mA    35.1mA     455.6uA
-840mV    490.7uA    13.24mA    11.36uA
-760mV    27.33uA    2.767mA    731.6nA
-640mV    346.7nA    134.1uA    731.6nA
0V        0A         15.13nA    0A
[Ramp]
| variable   typ   min   max
dV/dt_r  0.12041/1.21431n   78.19771m/1.61186n  0.15640/1.21677n
dV/dt_f  20.46000m/0.77208n  14.10000m/1.34222n  26.88000m/0.63546n
R_load = 50.000000
|End [Model] io8usb_vbus
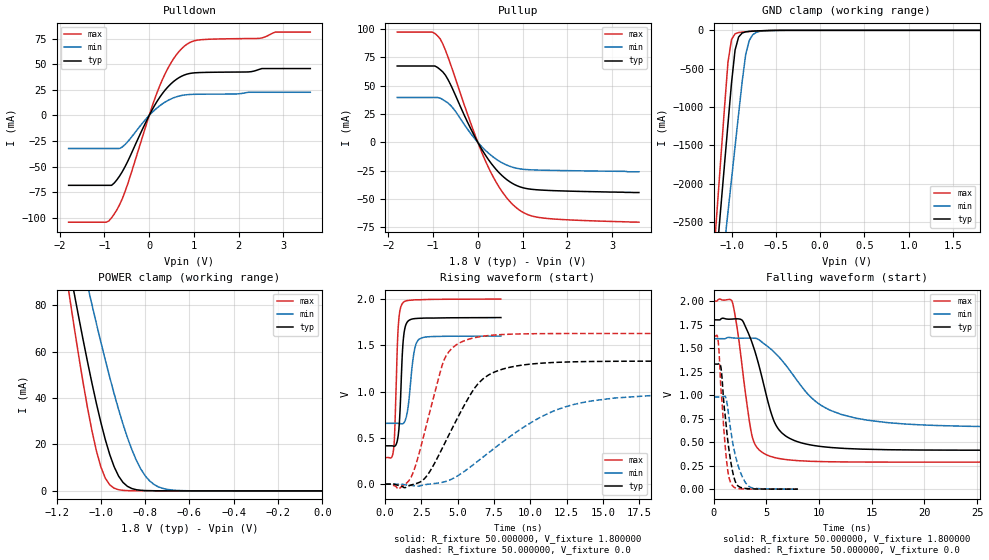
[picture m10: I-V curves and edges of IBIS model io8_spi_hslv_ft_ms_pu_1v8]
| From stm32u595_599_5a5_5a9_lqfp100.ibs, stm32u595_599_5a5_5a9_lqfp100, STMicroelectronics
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|   Model io8_spi_hslv_ft_ms_pu_1v8
[Model]  io8_spi_hslv_ft_ms_pu_1v8
Model_type I/O
Polarity   Non-Inverting
Enable   Active-Low
Vinl =   0.540000V
Vinh =   1.260000V
Vmeas =  0.900000V
Cref =   50.000000pF
Rref =   100.000000M
Vref =   0.0V
C_comp   3.338700pF   3.332500pF   3.379000pF
[Temperature Range]   25.000000   0.140000k   -40.000000
[Pullup Reference]   1.800000V   1.600000V   2.000000V
[Pulldown Reference]   0.0V   0.0V   0.0V
[POWER Clamp Reference]   1.800000V   1.600000V   2.000000V
[GND Clamp Reference]   0.0V   0.0V   0.0V
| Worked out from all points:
|   slope of the pulldown table from 0 to 0.27 V, typ, clamps not added: 13.6 ohm
|   slope of the pullup table from 0 to 0.27 V, typ, clamps not added: 15.9 ohm
|   GND clamp passes 1 mA (typ) near -0.51 V on its own axis
|   POWER clamp passes 1 mA (typ) near -0.86 V on its own axis
|   rising waveform, R_fixture 50.000000, V_fixture 1.800000: 20-80 % time 240ps typ, 385ps min, 214ps max; typ from 0.414 V to 1.8 V
|   rising waveform, R_fixture 50.000000, V_fixture 0.0: 20-80 % time 2.75ns typ, 5.57ns min, 1.64ns max; typ from 0 V to 1.33 V
|   falling waveform, R_fixture 50.000000, V_fixture 1.800000: 20-80 % time 2.12ns typ, 4.8ns min, 1.23ns max; typ from 1.8 V to 0.414 V
|   falling waveform, R_fixture 50.000000, V_fixture 0.0: 20-80 % time 794ps typ, 1.06ns min, 622ps max; typ from 1.33 V to 0 V
[Pulldown]
|Voltage   I(typ)   I(min)   I(max)
-1.8V     -68.38mA   -32.32mA   -104.4mA
-960mV    -68.38mA   -32.32mA   -104.4mA
-780mV    -66.07mA   -32.32mA   -96.42mA
-540mV    -50.22mA   -28.51mA   -74.66mA
0V        0A         0A         0A
240mV     18.04mA    9.599mA    29.41mA
480mV     30.68mA    16.02mA    50.95mA
780mV     39.47mA    19.98mA    67.56mA
1.14V     41.98mA    20.78mA    74.01mA
2.46V     45.09mA    22.68mA    75.44mA
2.82V     45.89mA    22.68mA    81.56mA
3.6V      45.89mA    22.68mA    81.56mA
[Pullup]
|Voltage   I(typ)   I(min)   I(max)
-1.8V     67.41mA    39.62mA    97.35mA
-1.02V    67.41mA    39.62mA    97.35mA
-840mV    64.22mA    39.02mA    91.35mA
-660mV    55.02mA    34.57mA    74.64mA
-180mV    13.77mA    8.913mA    19.32mA
180mV     -11.9mA    -7.442mA   -17.26mA
360mV     -21.65mA   -13.44mA   -31.67mA
540mV     -29.31mA   -18.02mA   -43.36mA
900mV     -38.69mA   -23.13mA   -58.99mA
1.14V     -41.14mA   -24.16mA   -64.17mA
1.5V      -42.31mA   -24.64mA   -67mA
3.6V      -44.3mA    -26mA      -70.5mA
[GND_clamp]
|Voltage   I(typ)   I(min)   I(max)
-1.8V     -9.908A    -9.683A    -9.994A
-1.2V     -3.383A    -4.084A    -2.934A
-1.16V    -2.841A    -3.655A    -2.294A
-1.12V    -2.299A    -3.226A    -1.656A
-1.04V    -1.218A    -2.369A    -414.2mA
-1V       -684.7mA   -1.941A    -119.2mA
-960mV    -257.2mA   -1.514A    -45.66mA
-920mV    -87.03mA   -1.089A    -28.93mA
-840mV    -19.35mA   -312.8mA   -18.96mA
-800mV    -13.55mA   -132.4mA   -15.49mA
-720mV    -8.042mA   -25.66mA   -9.49mA
1.8V      0A         13.64nA    0A
[POWER_clamp]
|Voltage   I(typ)   I(min)   I(max)
-1.8V     470.9mA    433.7mA    554.6mA
-1.14V    95.28mA    122.7mA    82.88mA
-1.12V    85mA       114mA      70.34mA
-1.06V    55.55mA    88.43mA    35.73mA
-1.04V    46.38mA    80.17mA    25.83mA
-1V       29.54mA    64.14mA    10.37mA
-940mV    10.43mA    41.88mA    1.177mA
-900mV    3.66mA     28.79mA    250.5uA
-840mV    527.2uA    13.26mA    95.94uA
-800mV    154uA      6.55mA     88.41uA
-740mV    59.83uA    1.741mA    70.38uA
0V        0A         18.18nA    0A
[Ramp]
| variable   typ   min   max
dV/dt_r  0.79756/2.74710n   0.58806/5.56486n   0.97651/1.63782n
dV/dt_f  0.83131/2.11280n   0.56548/4.78937n   1.02742/1.22528n
R_load = 50.000000
[Rising Waveform]
R_fixture= 50.000000
V_fixture= 1.800000
V_fixture_min= 1.600000
V_fixture_max= 2.000000
|time   V(typ)   V(min)   V(max)
0s        414.5mV    657.5mV    287.6mV
576.6ps   411mV      657.6mV    369.8mV
656.7ps   410.7mV    657.7mV    563.2mV
896.9ps   522.4mV    657.2mV    1.688V
1.009ns   746.3mV    655.4mV    1.867V
1.201ns   1.457V     653.3mV    1.955V
1.457ns   1.734V     726.9mV    1.981V
1.986ns   1.788V     1.421V     1.991V
2.338ns   1.792V     1.566V     1.992V
7.976ns   1.8V       1.6V       2V
[Rising Waveform]
R_fixture= 50.000000
V_fixture= 0.0
V_fixture_min= 0.0
V_fixture_max= 0.0
|time   V(typ)   V(min)   V(max)
0s        423.3uV    505.2uV    380.1uV
900.9ps   -12.64mV   726.5uV    -54.05mV
1.602ns   -20.29mV   -11.32mV   31.45mV
2.703ns   58.59mV    -7.418mV   550.9mV
4.204ns   473mV      30.43mV    1.387V
6.206ns   1.047V     226.4mV    1.584V
7.808ns   1.228V     422.1mV    1.614V
10.91ns   1.309V     739.8mV    1.627V
15.72ns   1.327V     928.9mV    1.628V
49.85ns   1.33V      980.7mV    1.628V
[Falling Waveform]
R_fixture= 50.000000
V_fixture= 1.800000
V_fixture_min= 1.600000
V_fixture_max= 2.000000
|time   V(typ)   V(min)   V(max)
0s        1.8V       1.6V       2V
1.702ns   1.808V     1.61V      2.005V
2.202ns   1.811V     1.605V     1.724V
2.703ns   1.795V     1.605V     1.294V
3.704ns   1.533V     1.605V     535.7mV
5.506ns   789mV      1.481V     344.7mV
6.807ns   566.9mV    1.323V     315.7mV
9.91ns    457.7mV    912.9mV    294.4mV
14.61ns   424.4mV    733mV      288.5mV
49.85ns   414.5mV    657.5mV    287.6mV
[Falling Waveform]
R_fixture= 50.000000
V_fixture= 0.0
V_fixture_min= 0.0
V_fixture_max= 0.0
|time   V(typ)   V(min)   V(max)
0s        1.33V      980.7mV    1.628V
384.4ps   1.33V      980.8mV    1.6V
496.5ps   1.335V     980.8mV    1.465V
656.7ps   1.308V     980.7mV    1.105V
1.217ns   632.2mV    938.8mV    299.6mV
1.409ns   445mV      788.1mV    144.4mV
1.666ns   257.5mV    584.8mV    54.82mV
2.194ns   47.97mV    294.5mV    8.669mV
3.315ns   5.369mV    31.11mV    1.919mV
7.976ns   423.3uV    505.2uV    380.1uV
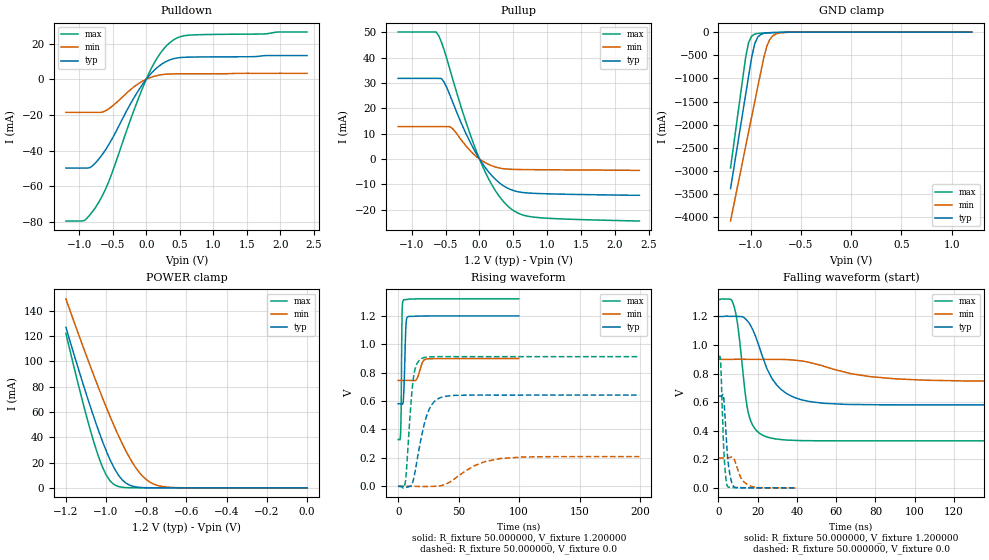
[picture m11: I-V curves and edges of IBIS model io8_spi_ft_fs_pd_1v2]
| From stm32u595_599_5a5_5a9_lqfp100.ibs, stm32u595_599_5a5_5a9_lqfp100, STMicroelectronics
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|   Model io8_spi_ft_fs_pd_1v2
[Model]  io8_spi_ft_fs_pd_1v2
Model_type I/O
Polarity   Non-Inverting
Enable   Active-Low
Vinl =   0.360000V
Vinh =   0.840000V
Vmeas =  0.600000V
Cref =   50.000000pF
Rref =   100.000000M
Vref =   0.0V
C_comp   3.132800pF   3.069700pF   3.178000pF
[Temperature Range]   25.000000   0.140000k   -40.000000
[Pullup Reference]   1.200000V   0.900000V   1.320000V
[Pulldown Reference]   0.0V   0.0V   0.0V
[POWER Clamp Reference]   1.200000V   0.900000V   1.320000V
[GND Clamp Reference]   0.0V   0.0V   0.0V
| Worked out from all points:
|   slope of the pulldown table from 0 to 0.18 V, typ, clamps not added: 25.4 ohm
|   slope of the pullup table from 0 to 0.18 V, typ, clamps not added: 27.8 ohm
|   GND clamp passes 1 mA (typ) near -0.51 V on its own axis
|   POWER clamp passes 1 mA (typ) near -0.86 V on its own axis
|   rising waveform, R_fixture 50.000000, V_fixture 1.200000: 20-80 % time 1.28ns typ, 3.42ns min, 629ps max; typ from 0.581 V to 1.2 V
|   rising waveform, R_fixture 50.000000, V_fixture 0.0: 20-80 % time 9.76ns typ, 24.9ns min, 4.73ns max; typ from 0 V to 0.642 V
|   falling waveform, R_fixture 50.000000, V_fixture 1.200000: 20-80 % time 12.3ns typ, 30.4ns min, 5.21ns max; typ from 1.2 V to 0.581 V
|   falling waveform, R_fixture 50.000000, V_fixture 0.0: 20-80 % time 2.15ns typ, 4.1ns min, 1.55ns max; typ from 0.642 V to 0 V
[Pulldown]
|Voltage   I(typ)   I(min)   I(max)
-1.2V     -49.85mA   -18.57mA   -79.56mA
-920mV    -49.85mA   -18.57mA   -79.19mA
-840mV    -49.59mA   -18.57mA   -76.08mA
-720mV    -45.32mA   -18.57mA   -69.74mA
-560mV    -36.71mA   -16.58mA   -57.44mA
-200mV    -11.43mA   -4.74mA    -19.03mA
0V        -10fA      -600fA     0A
160mV     6.476mA    2.075mA    11.78mA
360mV     10.99mA    2.989mA    20.81mA
480mV     12.07mA    3.053mA    23.52mA
640mV     12.42mA    3.074mA    24.76mA
2.4V      13.31mA    3.34mA     26.51mA
[Pullup]
|Voltage   I(typ)   I(min)   I(max)
-1.2V     31.79mA    12.78mA    50.08mA
-640mV    31.79mA    12.78mA    50.08mA
-600mV    31.79mA    12.78mA    48.52mA
-520mV    30.2mA     12.78mA    42.85mA
-400mV    22.73mA    12.06mA    31.92mA
-200mV    10.05mA    5.174mA    14.59mA
0V        0A         0A         0A
240mV     -8.14mA    -3.2mA     -12.72mA
480mV     -12.27mA   -4.078mA   -19.94mA
640mV     -13.22mA   -4.169mA   -22.09mA
880mV     -13.63mA   -4.232mA   -23.14mA
2.36V     -14.3mA    -4.5mA     -24.46mA
[GND_clamp]
|Voltage   I(typ)   I(min)   I(max)
-1.2V     -3.379A    -4.076A    -2.932A
-1.05V    -1.35A     -2.47A     -550.7mA
-1.02V    -947.8mA   -2.15A     -221.5mA
-990mV    -552.4mA   -1.829A    -88.45mA
-960mV    -255.3mA   -1.51A     -44.89mA
-930mV    -111.8mA   -1.191A    -30.69mA
-870mV    -28.36mA   -564.6mA   -21.36mA
-840mV    -18.66mA   -309.5mA   -18.51mA
-810mV    -14.08mA   -161.6mA   -15.94mA
-780mV    -11.38mA   -83.33mA   -13.55mA
-600mV    -3.019mA   -4.329mA   -3.104mA
1.2V      30.28uA    18.17uA    37.27uA
[POWER_clamp]
|Voltage   I(typ)   I(min)   I(max)
-1.2V     127mA      149.4mA    122.2mA
-1.12V    84.97mA    114mA      70.27mA
-1.06V    55.51mA    88.42mA    35.67mA
-1.02V    37.63mA    72.04mA    17.17mA
-1V       29.51mA    64.13mA    10.3mA
-960mV    15.69mA    48.99mA    2.571mA
-900mV    3.624mA    28.77mA    182.8uA
-840mV    490.7uA    13.24mA    11.35uA
-800mV    116.8uA    6.532mA    1.77uA
-740mV    13.2uA     1.724mA    109.1nA
-620mV    167.4nA    79.36uA    0A
0V        0A         17.87nA    0A
[Ramp]
| variable   typ   min   max
dV/dt_r  0.38523/9.74751n   0.12536/24.90779n   0.54788/4.72368n
dV/dt_f  0.37090/12.28496n   92.59200m/30.37966n 0.59417/5.19662n
R_load = 50.000000
[Rising Waveform]
R_fixture= 50.000000
V_fixture= 1.200000
V_fixture_min= 0.900000
V_fixture_max= 1.320000
|time   V(typ)   V(min)   V(max)
0s        581.3mV    745.2mV    329.2mV
2.002ns   581.4mV    745.2mV    379.1mV
2.402ns   581.3mV    745.2mV    526.7mV
3.203ns   579mV      745.2mV    1.216V
4.404ns   627.8mV    745.2mV    1.311V
6.206ns   1.097V     745.2mV    1.314V
7.608ns   1.191V     745.2mV    1.316V
14.81ns   1.198V     749.3mV    1.319V
22.82ns   1.199V     895.8mV    1.319V
99.7ns    1.2V       899.5mV    1.319V
[Rising Waveform]
R_fixture= 50.000000
V_fixture= 0.0
V_fixture_min= 0.0
V_fixture_max= 0.0
|time   V(typ)   V(min)   V(max)
0s        1.321uV    940.5nV    27.8nV
5.606ns   -2.764mV   548.6nV    15.1mV
12.41ns   40.35mV    42.85uV    752.1mV
14.41ns   124.8mV    -337.3uV   839.9mV
19.22ns   351.7mV    -1.219mV   899.1mV
27.23ns   567.2mV    -384.9uV   911.6mV
39.64ns   634.6mV    15.91mV    912.7mV
63.26ns   642.1mV    146.1mV    912.8mV
84.08ns   642mV      195.2mV    912.8mV
199.4ns   642.1mV    209.1mV    912.8mV
[Falling Waveform]
R_fixture= 50.000000
V_fixture= 1.200000
V_fixture_min= 0.900000
V_fixture_max= 1.320000
|time   V(typ)   V(min)   V(max)
0s        1.2V       899.5mV    1.319V
8.008ns   1.201V     900.1mV    1.269V
10.01ns   1.2V       900.6mV    1.117V
15.22ns   1.161V     899.8mV    524.6mV
18.42ns   1.077V     899.8mV    416.8mV
24.42ns   844mV      899.7mV    357.7mV
34.83ns   659.5mV    898.1mV    334.5mV
53.25ns   592.5mV    853.3mV    329.5mV
90.49ns   581.5mV    762.8mV    329.2mV
199.4ns   581.3mV    745.2mV    329.2mV
[Falling Waveform]
R_fixture= 50.000000
V_fixture= 0.0
V_fixture_min= 0.0
V_fixture_max= 0.0
|time   V(typ)   V(min)   V(max)
0s        642.1mV    209.1mV    912.8mV
1.121ns   641.7mV    209.1mV    870.9mV
2.563ns   642.4mV    209.1mV    304.8mV
3.604ns   436.7mV    208.9mV    89.14mV
4.565ns   229.2mV    208.9mV    10.27mV
6.086ns   74.51mV    213.7mV    3.481mV
7.848ns   6.246mV    203.9mV    1.637mV
11.45ns   1.479mV    69.61mV    605.8uV
15.3ns    746.2uV    18.76mV    262.9uV
39.88ns   1.321uV    940.5nV    27.8nV
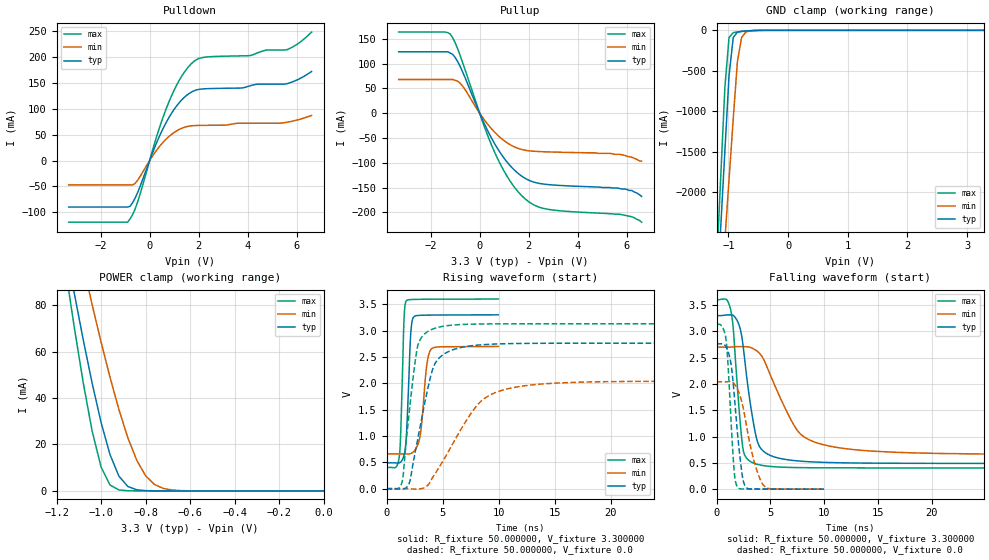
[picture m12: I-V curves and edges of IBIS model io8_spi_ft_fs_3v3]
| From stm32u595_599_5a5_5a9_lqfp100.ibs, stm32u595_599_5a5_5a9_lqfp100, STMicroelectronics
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|   Model io8_spi_ft_fs_3v3
[Model]  io8_spi_ft_fs_3v3
Model_type I/O
Polarity   Non-Inverting
Enable   Active-Low
Vinl =   0.990000V
Vinh =   2.310000V
Vmeas =  1.650000V
Cref =   50.000000pF
Rref =   100.000000M
Vref =   0.0V
C_comp   3.495300pF   3.468500pF   3.534700pF
[Temperature Range]   25.000000   0.140000k   -40.000000
[Pullup Reference]   3.300000V   2.700000V   3.600000V
[Pulldown Reference]   0.0V   0.0V   0.0V
[POWER Clamp Reference]   3.300000V   2.700000V   3.600000V
[GND Clamp Reference]   0.0V   0.0V   0.0V
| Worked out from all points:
|   slope of the pulldown table from 0 to 0.495 V, typ, clamps not added: 8.73 ohm
|   slope of the pullup table from 0 to 0.495 V, typ, clamps not added: 9.64 ohm
|   GND clamp passes 1 mA (typ) near -0.50 V on its own axis
|   POWER clamp passes 1 mA (typ) near -0.85 V on its own axis
|   rising waveform, R_fixture 50.000000, V_fixture 3.300000: 20-80 % time 323ps typ, 519ps min, 256ps max; typ from 0.49 V to 3.3 V
|   rising waveform, R_fixture 50.000000, V_fixture 0.0: 20-80 % time 1.6ns typ, 3.59ns min, 973ps max; typ from 0 V to 2.76 V
|   falling waveform, R_fixture 50.000000, V_fixture 3.300000: 20-80 % time 1.16ns typ, 2.96ns min, 706ps max; typ from 3.3 V to 0.49 V
|   falling waveform, R_fixture 50.000000, V_fixture 0.0: 20-80 % time 758ps typ, 1.29ns min, 517ps max; typ from 2.76 V to 0 V
[Pulldown]
|Voltage   I(typ)   I(min)   I(max)
-3.3V     -89.71mA   -47.06mA   -119mA
-900mV    -89.71mA   -47.06mA   -119mA
-700mV    -81.75mA   -47.06mA   -104.8mA
-500mV    -62.92mA   -38.71mA   -81.44mA
300mV     36.2mA     21.01mA    48.7mA
800mV     84.06mA    46.96mA    114.8mA
1.3V      116.7mA    62.08mA    162.3mA
1.8V      134.4mA    67.38mA    191.2mA
2.2V      138.3mA    67.91mA    199.2mA
4.1V      144.4mA    71.97mA    202.7mA
5.6V      148.4mA    73.95mA    213.9mA
6.6V      171.9mA    87.1mA     247.9mA
[Pullup]
|Voltage   I(typ)   I(min)   I(max)
-3.3V     123.9mA    67.96mA    163.6mA
-1.2V     121.4mA    67.96mA    159.8mA
-1V       112.5mA    66.35mA    142.3mA
-700mV    83.97mA    54.94mA    102.9mA
200mV     -22.26mA   -14.13mA   -28.39mA
700mV     -69mA      -42.82mA   -88.5mA
1.3V      -109.1mA   -65.19mA   -141.4mA
1.9V      -132.8mA   -75.24mA   -174.9mA
2.7V      -143.6mA   -78mA      -193.3mA
5.6V      -151mA     -83mA      -204mA
6.2V      -156mA     -89mA      -209mA
6.6V      -168mA     -97mA      -220mA
[GND_clamp]
|Voltage   I(typ)   I(min)   I(max)
-3.3V     -9.098A    -9.372A    -9.671A
-1.2V     -3.386A    -4.091A    -2.933A
-1.13V    -2.437A    -3.34A     -1.815A
-1.06V    -1.49A     -2.588A    -705.6mA
-990mV    -555.7mA   -1.839A    -89.03mA
-920mV    -88.12mA   -1.093A    -28.78mA
-850mV    -22.35mA   -387.4mA   -19.84mA
-780mV    -12.12mA   -88mA      -13.87mA
-710mV    -7.709mA   -22.52mA   -8.846mA
-640mV    -4.545mA   -7.864mA   -4.87mA
-360mV    -31.12uA   -173.5uA   -8.496uA
3.28V     0A         14.15nA    -7.901nA
[POWER_clamp]
|Voltage   I(typ)   I(min)   I(max)
-3.28V    1.355A     1.167A     1.664A
-1.16V    105.7mA    131.6mA    95.69mA
-1.12V    84.97mA    114mA      70.27mA
-1.08V    65.05mA    96.83mA    46.54mA
-1.04V    46.34mA    80.15mA    25.76mA
-1V       29.51mA    64.13mA    10.3mA
-960mV    15.69mA    48.99mA    2.571mA
-920mV    6.373mA    35.1mA     455.6uA
-840mV    490.7uA    13.24mA    11.36uA
-760mV    27.33uA    2.767mA    279.3nA
-640mV    348nA      134.1uA    17.46nA
0V        0A         19.95nA    0A
[Ramp]
| variable   typ   min   max
dV/dt_r  1.65714/1.59957n   1.22460/3.58517n   1.87854/0.97292n
dV/dt_f  1.68605/1.16017n   1.22410/2.95632n   1.91788/0.70468n
R_load = 50.000000
[Rising Waveform]
R_fixture= 50.000000
V_fixture= 3.300000
V_fixture_min= 2.700000
V_fixture_max= 3.600000
|time   V(typ)   V(min)   V(max)
0s        489.9mV    659.8mV    403.5mV
1.141ns   491.2mV    659.8mV    616.9mV
1.562ns   633.7mV    659.5mV    3.226V
1.762ns   976.1mV    658.4mV    3.565V
2.142ns   2.884V     665.5mV    3.59V
2.402ns   3.255V     700.5mV    3.593V
3.023ns   3.292V     1.041V     3.595V
3.564ns   3.295V     2.302V     3.596V
3.944ns   3.296V     2.64V      3.597V
9.97ns    3.3V       2.7V       3.6V
[Rising Waveform]
R_fixture= 50.000000
V_fixture= 0.0
V_fixture_min= 0.0
V_fixture_max= 0.0
|time   V(typ)   V(min)   V(max)
0s        4.191uV    5.103uV    1.465uV
1.401ns   -9.732mV   80.96uV    132.9mV
2.002ns   91.11mV    -2.094mV   1.407V
2.503ns   633.8mV    -7.866mV   2.333V
2.803ns   961.8mV    -7.307mV   2.728V
3.904ns   2.108V     132.7mV    3.011V
4.505ns   2.434V     342.7mV    3.058V
8.208ns   2.727V     1.615V     3.126V
11.71ns   2.756V     1.934V     3.13V
49.85ns   2.762V     2.041V     3.131V
[Falling Waveform]
R_fixture= 50.000000
V_fixture= 3.300000
V_fixture_min= 2.700000
V_fixture_max= 3.600000
|time   V(typ)   V(min)   V(max)
0s        3.3V       2.7V       3.6V
1.301ns   3.312V     2.701V     3.422V
1.602ns   3.297V     2.706V     2.937V
2.102ns   3.116V     2.71V      1.505V
2.603ns   2.491V     2.708V     651.1mV
3.704ns   976.1mV    2.634V     477.2mV
4.705ns   671.4mV    2.315V     438.4mV
7.508ns   537.9mV    1.118V     410.3mV
10.51ns   506.6mV    818.1mV    405.2mV
49.85ns   489.9mV    659.8mV    403.5mV
[Falling Waveform]
R_fixture= 50.000000
V_fixture= 0.0
V_fixture_min= 0.0
V_fixture_max= 0.0
|time   V(typ)   V(min)   V(max)
0s        2.762V     2.041V     3.131V
880.9ps   2.703V     2.041V     2.848V
1.341ns   2.384V     2.043V     1.326V
1.622ns   1.845V     2.007V     390.8mV
1.942ns   1.077V     1.9V       41.63mV
2.342ns   331.3mV    1.657V     3.92mV
2.623ns   74.5mV     1.391V     2.717mV
3.383ns   3.422mV    612mV      1.524mV
4.324ns   1.606mV    84.52mV    967.4uV
9.97ns    4.191uV    5.103uV    1.465uV
